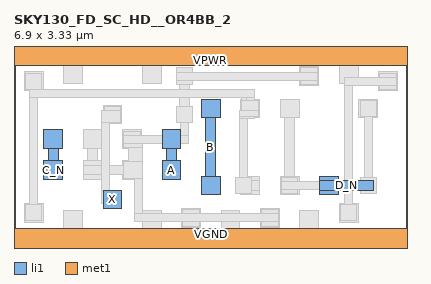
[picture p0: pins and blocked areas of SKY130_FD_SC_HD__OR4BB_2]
MACRO SKY130_FD_SC_HD__OR4BB_2
 CLASS CORE ;
 FOREIGN SKY130_FD_SC_HD__OR4BB_2 0 0 ;
 SIZE 6.9 BY 3.33 ;
 ORIGIN 0 0 ;
 SYMMETRY X Y R90 ;
 SITE unit ;
  PIN VPWR
   DIRECTION INOUT ;
   USE POWER ;
   SHAPE ABUTMENT ;
    PORT
     CLASS CORE ;
       LAYER li1 ;
        RECT 0.00000000 3.09000000 6.90000000 3.57000000 ;
       LAYER met1 ;
        RECT 0.00000000 3.09000000 6.90000000 3.57000000 ;
    END
  END VPWR

  PIN VGND
   DIRECTION INOUT ;
   USE POWER ;
   SHAPE ABUTMENT ;
    PORT
     CLASS CORE ;
       LAYER li1 ;
        RECT 0.00000000 -0.24000000 6.90000000 0.24000000 ;
       LAYER met1 ;
        RECT 0.00000000 -0.24000000 6.90000000 0.24000000 ;
    END
  END VGND

  PIN X
   DIRECTION INOUT ;
   USE SIGNAL ;
   SHAPE ABUTMENT ;
    PORT
     CLASS CORE ;
       LAYER li1 ;
        RECT 1.56000000 0.58000000 1.89000000 0.91000000 ;
    END
  END X

  PIN D_N
   DIRECTION INOUT ;
   USE SIGNAL ;
   SHAPE ABUTMENT ;
    PORT
     CLASS CORE ;
       LAYER li1 ;
        RECT 5.35500000 0.82500000 5.68500000 0.90500000 ;
        RECT 5.35500000 0.90500000 6.29500000 1.07500000 ;
        RECT 5.35500000 1.07500000 5.68500000 1.15500000 ;
    END
  END D_N

  PIN B
   DIRECTION INOUT ;
   USE SIGNAL ;
   SHAPE ABUTMENT ;
    PORT
     CLASS CORE ;
       LAYER li1 ;
        RECT 3.28500000 0.82500000 3.61500000 1.15500000 ;
        RECT 3.36500000 1.15500000 3.53500000 2.17500000 ;
        RECT 3.28500000 2.17500000 3.61500000 2.50500000 ;
    END
  END B

  PIN C_N
   DIRECTION INOUT ;
   USE SIGNAL ;
   SHAPE ABUTMENT ;
    PORT
     CLASS CORE ;
       LAYER li1 ;
        RECT 0.52500000 1.09500000 0.85500000 1.42500000 ;
        RECT 0.60500000 1.42500000 0.77500000 1.63500000 ;
        RECT 0.52500000 1.63500000 0.85500000 1.96500000 ;
    END
  END C_N

  PIN A
   DIRECTION INOUT ;
   USE SIGNAL ;
   SHAPE ABUTMENT ;
    PORT
     CLASS CORE ;
       LAYER li1 ;
        RECT 2.59500000 1.09500000 2.92500000 1.42500000 ;
        RECT 2.67500000 1.42500000 2.84500000 1.63500000 ;
        RECT 2.59500000 1.63500000 2.92500000 1.96500000 ;
    END
  END A

 OBS
    LAYER polycont ;
     RECT 3.36500000 0.90500000 3.53500000 1.07500000 ;
     RECT 3.36500000 2.25500000 3.53500000 2.42500000 ;
     RECT 1.29500000 1.17500000 1.46500000 1.34500000 ;
     RECT 1.98500000 1.17500000 2.15500000 1.34500000 ;
     RECT 1.29500000 1.71500000 1.46500000 1.88500000 ;
     RECT 1.98500000 1.71500000 2.15500000 1.88500000 ;
     RECT 4.74500000 0.90500000 4.91500000 1.07500000 ;
     RECT 4.74500000 2.25500000 4.91500000 2.42500000 ;
     RECT 5.43500000 0.90500000 5.60500000 1.07500000 ;
     RECT 6.12500000 2.25500000 6.29500000 2.42500000 ;
     RECT 4.05500000 0.90500000 4.22500000 1.07500000 ;
     RECT 4.05500000 2.25500000 4.22500000 2.42500000 ;
     RECT 2.67500000 1.17500000 2.84500000 1.34500000 ;
     RECT 2.67500000 1.71500000 2.84500000 1.88500000 ;
     RECT 0.60500000 1.17500000 0.77500000 1.34500000 ;
     RECT 0.60500000 1.71500000 0.77500000 1.88500000 ;

    LAYER pdiffc ;
     RECT 5.09000000 2.82000000 5.26000000 2.99000000 ;
     RECT 6.47000000 2.73000000 6.64000000 2.90000000 ;
     RECT 0.95000000 2.86000000 1.12000000 3.03000000 ;
     RECT 2.33000000 2.86000000 2.50000000 3.03000000 ;
     RECT 5.78000000 2.86000000 5.95000000 3.03000000 ;
     RECT 0.26000000 2.73000000 0.43000000 2.90000000 ;
     RECT 1.64000000 2.15000000 1.81000000 2.32000000 ;

    LAYER ndiffc ;
     RECT 3.02000000 0.34000000 3.19000000 0.51000000 ;
     RECT 4.40000000 0.34000000 4.57000000 0.51000000 ;
     RECT 5.78000000 0.43000000 5.95000000 0.60000000 ;
     RECT 0.26000000 0.43000000 0.43000000 0.60000000 ;
     RECT 0.95000000 0.30000000 1.12000000 0.47000000 ;
     RECT 2.33000000 0.30000000 2.50000000 0.47000000 ;
     RECT 3.71000000 0.30000000 3.88000000 0.47000000 ;
     RECT 5.09000000 0.30000000 5.26000000 0.47000000 ;
     RECT 1.64000000 0.66000000 1.81000000 0.83000000 ;

    LAYER li1 ;
     RECT 3.28500000 0.82500000 3.61500000 1.15500000 ;
     RECT 3.36500000 1.15500000 3.53500000 2.17500000 ;
     RECT 3.28500000 2.17500000 3.61500000 2.50500000 ;
     RECT 2.94000000 0.26000000 3.27000000 0.59000000 ;
     RECT 4.32000000 0.26000000 4.65000000 0.59000000 ;
     RECT 1.21500000 1.09500000 1.54500000 1.17500000 ;
     RECT 1.90500000 1.09500000 2.23500000 1.17500000 ;
     RECT 1.21500000 1.17500000 2.23500000 1.34500000 ;
     RECT 1.21500000 1.34500000 1.54500000 1.42500000 ;
     RECT 1.90500000 1.34500000 2.23500000 1.42500000 ;
     RECT 1.29500000 1.42500000 1.46500000 1.63500000 ;
     RECT 1.21500000 1.63500000 1.54500000 1.96500000 ;
     RECT 1.90500000 1.63500000 2.23500000 1.96500000 ;
     RECT 2.90500000 2.15000000 3.07500000 2.99000000 ;
     RECT 5.01000000 2.74000000 5.34000000 3.07000000 ;
     RECT 5.70000000 0.35000000 6.03000000 0.68000000 ;
     RECT 4.66500000 0.82500000 4.99500000 1.15500000 ;
     RECT 4.74500000 1.15500000 4.91500000 2.17500000 ;
     RECT 4.66500000 2.17500000 4.99500000 2.50500000 ;
     RECT 6.39000000 2.65000000 6.72000000 2.98000000 ;
     RECT 0.87000000 2.78000000 1.20000000 3.09000000 ;
     RECT 2.25000000 2.78000000 2.58000000 3.09000000 ;
     RECT 5.70000000 2.78000000 6.03000000 3.09000000 ;
     RECT 0.00000000 3.09000000 6.90000000 3.57000000 ;
     RECT 5.35500000 0.82500000 5.68500000 0.90500000 ;
     RECT 5.35500000 0.90500000 6.29500000 1.07500000 ;
     RECT 5.35500000 1.07500000 5.68500000 1.15500000 ;
     RECT 6.04500000 2.17500000 6.37500000 2.50500000 ;
     RECT 0.18000000 0.35000000 0.51000000 0.68000000 ;
     RECT 3.97500000 0.82500000 4.30500000 0.90500000 ;
     RECT 3.94000000 0.90500000 4.30500000 1.07500000 ;
     RECT 3.97500000 1.07500000 4.30500000 1.15500000 ;
     RECT 3.97500000 2.17500000 4.30500000 2.50500000 ;
     RECT 0.18000000 2.65000000 0.51000000 2.98000000 ;
     RECT 0.00000000 -0.24000000 6.90000000 0.24000000 ;
     RECT 0.87000000 0.24000000 1.20000000 0.55000000 ;
     RECT 2.25000000 0.24000000 2.58000000 0.55000000 ;
     RECT 3.63000000 0.24000000 3.96000000 0.55000000 ;
     RECT 5.01000000 0.24000000 5.34000000 0.55000000 ;
     RECT 2.59500000 1.09500000 2.92500000 1.42500000 ;
     RECT 2.67500000 1.42500000 2.84500000 1.63500000 ;
     RECT 2.59500000 1.63500000 2.92500000 1.96500000 ;
     RECT 1.56000000 0.58000000 1.89000000 0.91000000 ;
     RECT 1.56000000 2.07000000 1.89000000 2.40000000 ;
     RECT 0.52500000 1.09500000 0.85500000 1.42500000 ;
     RECT 0.60500000 1.42500000 0.77500000 1.63500000 ;
     RECT 0.52500000 1.63500000 0.85500000 1.96500000 ;

    LAYER viali ;
     RECT 3.02000000 0.34000000 3.19000000 0.51000000 ;
     RECT 4.40000000 0.34000000 4.57000000 0.51000000 ;
     RECT 1.98500000 1.17500000 2.15500000 1.34500000 ;
     RECT 1.98500000 1.71500000 2.15500000 1.88500000 ;
     RECT 2.90500000 2.15000000 3.07500000 2.32000000 ;
     RECT 2.90500000 2.82000000 3.07500000 2.99000000 ;
     RECT 5.09000000 2.82000000 5.26000000 2.99000000 ;
     RECT 5.78000000 0.43000000 5.95000000 0.60000000 ;
     RECT 4.74500000 0.90500000 4.91500000 1.07500000 ;
     RECT 6.47000000 2.73000000 6.64000000 2.90000000 ;
     RECT 2.33000000 3.24500000 2.50000000 3.41500000 ;
     RECT 6.12500000 0.90500000 6.29500000 1.07500000 ;
     RECT 6.12500000 2.25500000 6.29500000 2.42500000 ;
     RECT 0.26000000 0.43000000 0.43000000 0.60000000 ;
     RECT 3.94000000 0.90500000 4.11000000 1.07500000 ;
     RECT 4.05500000 2.25500000 4.22500000 2.42500000 ;
     RECT 0.26000000 2.73000000 0.43000000 2.90000000 ;
     RECT 5.09000000 -0.08500000 5.26000000 0.08500000 ;
     RECT 1.64000000 0.66000000 1.81000000 0.83000000 ;
     RECT 1.64000000 2.15000000 1.81000000 2.32000000 ;

    LAYER met1 ;
     RECT 3.99500000 2.48500000 4.07000000 2.54000000 ;
     RECT 2.96000000 0.28000000 3.25000000 0.35500000 ;
     RECT 4.34000000 0.28000000 4.63000000 0.35500000 ;
     RECT 2.11500000 0.35500000 4.63000000 0.49500000 ;
     RECT 2.96000000 0.49500000 3.25000000 0.57000000 ;
     RECT 4.34000000 0.49500000 4.63000000 0.57000000 ;
     RECT 2.11500000 0.49500000 2.25500000 1.11500000 ;
     RECT 1.92500000 1.11500000 2.25500000 1.40500000 ;
     RECT 2.00000000 1.40500000 2.25500000 1.65500000 ;
     RECT 1.92500000 1.65500000 2.25500000 1.73000000 ;
     RECT 1.92500000 1.73000000 3.06000000 1.87000000 ;
     RECT 1.92500000 1.87000000 2.21500000 1.94500000 ;
     RECT 2.92000000 1.87000000 3.06000000 2.09000000 ;
     RECT 2.84500000 2.09000000 3.13500000 2.38000000 ;
     RECT 2.84500000 2.76000000 3.13500000 2.83500000 ;
     RECT 5.03000000 2.76000000 5.32000000 2.83500000 ;
     RECT 2.84500000 2.83500000 5.32000000 2.97500000 ;
     RECT 2.84500000 2.97500000 3.13500000 3.05000000 ;
     RECT 5.03000000 2.97500000 5.32000000 3.05000000 ;
     RECT 5.72000000 0.37000000 6.01000000 0.66000000 ;
     RECT 4.68500000 0.84500000 4.97500000 0.92000000 ;
     RECT 5.79500000 0.66000000 5.93500000 0.92000000 ;
     RECT 4.68500000 0.92000000 5.93500000 1.06000000 ;
     RECT 4.68500000 1.06000000 4.97500000 1.13500000 ;
     RECT 5.79500000 1.06000000 5.93500000 2.74500000 ;
     RECT 6.41000000 2.67000000 6.70000000 2.74500000 ;
     RECT 5.79500000 2.74500000 6.70000000 2.88500000 ;
     RECT 6.41000000 2.88500000 6.70000000 2.96000000 ;
     RECT 0.00000000 3.09000000 6.90000000 3.57000000 ;
     RECT 6.06500000 0.84500000 6.35500000 1.13500000 ;
     RECT 6.14000000 1.13500000 6.28000000 2.19500000 ;
     RECT 6.06500000 2.19500000 6.35500000 2.48500000 ;
     RECT 0.20000000 0.37000000 0.49000000 0.66000000 ;
     RECT 3.88000000 0.84500000 4.17000000 1.13500000 ;
     RECT 3.95500000 1.13500000 4.09500000 2.16500000 ;
     RECT 3.95500000 2.16500000 4.21000000 2.19500000 ;
     RECT 3.95500000 2.19500000 4.28500000 2.30500000 ;
     RECT 3.99500000 2.30500000 4.28500000 2.48500000 ;
     RECT 0.27500000 0.66000000 0.41500000 2.54000000 ;
     RECT 4.07000000 2.48500000 4.21000000 2.54000000 ;
     RECT 0.27500000 2.54000000 4.21000000 2.67000000 ;
     RECT 0.20000000 2.67000000 4.21000000 2.68000000 ;
     RECT 0.20000000 2.68000000 0.49000000 2.96000000 ;
     RECT 0.00000000 -0.24000000 6.90000000 0.24000000 ;
     RECT 1.58000000 0.60000000 1.87000000 0.67500000 ;
     RECT 1.54000000 0.67500000 1.87000000 0.89000000 ;
     RECT 1.54000000 0.89000000 1.68000000 2.09000000 ;
     RECT 1.54000000 2.09000000 1.87000000 2.30500000 ;
     RECT 1.58000000 2.30500000 1.87000000 2.38000000 ;

    LAYER via ;


    LAYER met2 ;


    LAYER via2 ;


    LAYER met3 ;


 END
END SKY130_FD_SC_HD__OR4BB_2
